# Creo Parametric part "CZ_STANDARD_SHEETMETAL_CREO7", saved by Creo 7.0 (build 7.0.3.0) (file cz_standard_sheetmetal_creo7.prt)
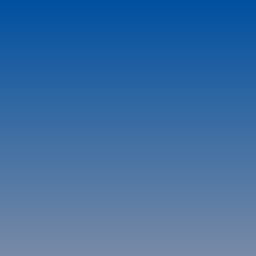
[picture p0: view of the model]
Units: Custom; MM, KILOGRAM, SECS

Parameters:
  BEARBEITER = "."
  ERSTELLUNGSDATUM = "."
  KONSTRUKTIONSGRUPPE = "."
  ZEICHNUNGSNUMMER = "000000-0000-000/01"
  TEILDOKUMENT = "001"
  VERSION = "01"
  MATERIALNUMMER = "000000-0000-000"
  KOMP_STUFE = "T"
  KOMP_CHAR = "M"
  BENENNUNG = "XXXXX"

Other parameters: PREIS, SMT_THICKNESS, SMT_PART_BEND_ALLOWANCE_FACTOR, SMT_DFLT_BEND_RADIUS, SMT_DFLT_BEND_ANGLE, SMT_DFLT_CRNR_REL_WIDTH, SMT_DFLT_CRNR_REL_DEPTH, SMT_DFLT_BEND_REL_WIDTH, SMT_DFLT_BEND_REL_DEPTH, SMT_DFLT_BEND_REL_ANGLE, SMT_GAP, SMT_DFLT_EDGE_TREA_WIDTH, SMT_DFLT_MITER_CUT_WIDTH, SMT_DFLT_MITER_CUT_OFFSET, SMT_DFLT_BEND_REL_LENGTH

Created from: CZ_STANDARD_SHEETMETAL_CREO4.PRT

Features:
  1. datum plane "Y-Z"
  2. datum plane "X-Z"
  3. datum plane "X-Y"
  4. coordinate system
  5. datum axis
  6. datum axis
  7. datum axis

Other named items: X0Y0Z0, X-ACHSE, Y-ACHSE, Z-ACHSE

Layers: ACHSEN, EBENEN, FLAECHEN, GEWINDE, KOORDSYS, KURVEN, PUNKTE, RUNDUNGEN, S_ACHSEN, S_EBENEN, S_KOORDSYS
